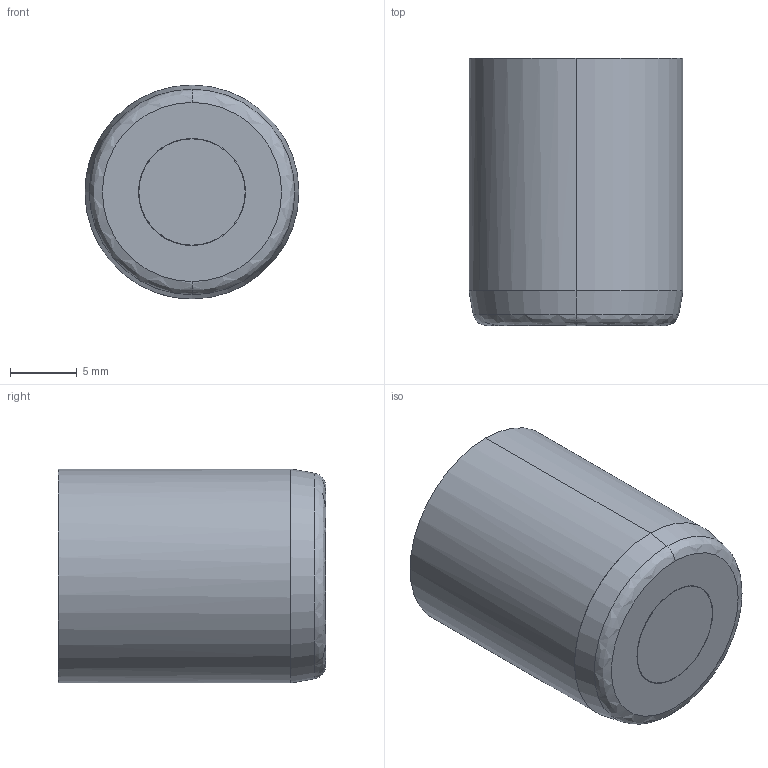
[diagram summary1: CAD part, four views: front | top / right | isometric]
IGES file: header records copied from the file, then geometry measured from it (millimetres).
Start section: START RECORD GO HERE.
Global section: file name: fa168710-20.igs; native system: DASSAULT SYSTEMES CATIA V5 R20 - www.3ds.com; preprocessor: CATIA Version 5 Release 20 ; author: Utente; organization: NB04-ASUS; date: 20201108.083525; units: millimetre
Bounding box: 16 x 20 x 16 mm (x, y, z)
Surface area: 2714.1 mm2 (no closed solid volume)
Topology: 0 solids, 0 shells, 499 faces, 2567 edges, 2559 vertices
Faces by surface type: revolution 270, plane 159, bspline 70
